VERSION 5.8 ;
BUSBITCHARS "[]" ;
DIVIDERCHAR "/" ;
UNITS
    DATABASE MICRONS 1000 ;
END UNITS

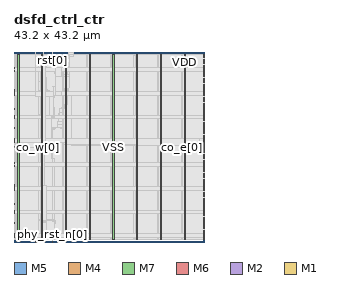
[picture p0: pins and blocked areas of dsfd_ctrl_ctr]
MACRO dsfd_ctrl_ctr
  FOREIGN dsfd_ctrl_ctr 0 0 ;
  CLASS BLOCK ;
  SIZE 43.2 BY 43.2 ;
  PIN ckh[0]
    DIRECTION INPUT ;
    USE SIGNAL ;
    PORT
      LAYER M5 ;
        RECT  6.72 43.008 6.744 43.2 ;
    END
  END ckh[0]
  PIN cks[0]
    DIRECTION INPUT ;
    USE SIGNAL ;
    PORT
      LAYER M5 ;
        RECT  4.8 43.008 4.824 43.2 ;
    END
  END cks[0]
  PIN co_e[0]
    DIRECTION INPUT ;
    USE SIGNAL ;
    PORT
      LAYER M4 ;
        RECT  43.008 21.552 43.2 21.576 ;
    END
  END co_e[0]
  PIN co_e[1]
    DIRECTION INPUT ;
    USE SIGNAL ;
    PORT
      LAYER M4 ;
        RECT  43.008 21.936 43.2 21.96 ;
    END
  END co_e[1]
  PIN co_w[0]
    DIRECTION INPUT ;
    USE SIGNAL ;
    PORT
      LAYER M4 ;
        RECT  0 21.552 0.192 21.576 ;
    END
  END co_w[0]
  PIN co_w[1]
    DIRECTION INPUT ;
    USE SIGNAL ;
    PORT
      LAYER M4 ;
        RECT  0 21.936 0.192 21.96 ;
    END
  END co_w[1]
  PIN k_oor[0]
    DIRECTION INPUT ;
    USE SIGNAL ;
    PORT
      LAYER M5 ;
        RECT  4.8 0 4.824 0.192 ;
    END
  END k_oor[0]
  PIN phy_rst_n[0]
    DIRECTION OUTPUT ;
    USE SIGNAL ;
    PORT
      LAYER M5 ;
        RECT  8.64 0 8.664 0.192 ;
    END
  END phy_rst_n[0]
  PIN rst[0]
    DIRECTION INPUT ;
    USE SIGNAL ;
    PORT
      LAYER M5 ;
        RECT  8.64 43.008 8.664 43.2 ;
    END
  END rst[0]
  PIN st[0]
    DIRECTION OUTPUT ;
    USE SIGNAL ;
    PORT
      LAYER M5 ;
        RECT  12.48 43.008 12.504 43.2 ;
    END
  END st[0]
  PIN st[1]
    DIRECTION OUTPUT ;
    USE SIGNAL ;
    PORT
      LAYER M5 ;
        RECT  13.44 43.008 13.464 43.2 ;
    END
  END st[1]
  PIN w_oor[0]
    DIRECTION INPUT ;
    USE SIGNAL ;
    PORT
      LAYER M5 ;
        RECT  6.72 0 6.744 0.192 ;
    END
  END w_oor[0]
  PIN VDD
    DIRECTION INOUT ;
    USE POWER ;
    PORT
      LAYER M7 ;
        RECT  38.656 0.531 38.944 42.669 ;
        RECT  27.856 0.531 28.144 42.669 ;
        RECT  17.056 0.531 17.344 42.669 ;
        RECT  6.256 0.531 6.544 42.669 ;
      LAYER M6 ;
        RECT  43.168 39.372 43.2 39.66 ;
        RECT  0 39.372 0.032 39.66 ;
        RECT  43.168 33.972 43.2 34.26 ;
        RECT  0 33.972 0.032 34.26 ;
        RECT  43.168 28.572 43.2 28.86 ;
        RECT  0 28.572 0.032 28.86 ;
        RECT  43.168 23.172 43.2 23.46 ;
        RECT  0 23.172 0.032 23.46 ;
        RECT  43.168 17.772 43.2 18.06 ;
        RECT  0 17.772 0.032 18.06 ;
        RECT  43.168 12.372 43.2 12.66 ;
        RECT  0 12.372 0.032 12.66 ;
        RECT  43.168 6.972 43.2 7.26 ;
        RECT  0 6.972 0.032 7.26 ;
        RECT  43.168 1.572 43.2 1.86 ;
        RECT  0 1.572 0.032 1.86 ;
      LAYER M2 ;
        RECT  43.182 42.381 43.2 42.399 ;
        RECT  0 42.381 0.018 42.399 ;
        RECT  43.182 41.841 43.2 41.859 ;
        RECT  0 41.841 0.018 41.859 ;
        RECT  43.182 41.301 43.2 41.319 ;
        RECT  0 41.301 0.018 41.319 ;
        RECT  43.182 40.761 43.2 40.779 ;
        RECT  0 40.761 0.018 40.779 ;
        RECT  43.182 40.221 43.2 40.239 ;
        RECT  0 40.221 0.018 40.239 ;
        RECT  43.182 39.681 43.2 39.699 ;
        RECT  0 39.681 0.018 39.699 ;
        RECT  43.182 39.141 43.2 39.159 ;
        RECT  0 39.141 0.018 39.159 ;
        RECT  43.182 38.601 43.2 38.619 ;
        RECT  0 38.601 0.018 38.619 ;
        RECT  43.182 38.061 43.2 38.079 ;
        RECT  0 38.061 0.018 38.079 ;
        RECT  43.182 37.521 43.2 37.539 ;
        RECT  0 37.521 0.018 37.539 ;
        RECT  43.182 36.981 43.2 36.999 ;
        RECT  0 36.981 0.018 36.999 ;
        RECT  43.182 36.441 43.2 36.459 ;
        RECT  0 36.441 0.018 36.459 ;
        RECT  43.182 35.901 43.2 35.919 ;
        RECT  0 35.901 0.018 35.919 ;
        RECT  43.182 35.361 43.2 35.379 ;
        RECT  0 35.361 0.018 35.379 ;
        RECT  43.182 34.821 43.2 34.839 ;
        RECT  0 34.821 0.018 34.839 ;
        RECT  43.182 34.281 43.2 34.299 ;
        RECT  0 34.281 0.018 34.299 ;
        RECT  43.182 33.741 43.2 33.759 ;
        RECT  0 33.741 0.018 33.759 ;
        RECT  43.182 33.201 43.2 33.219 ;
        RECT  0 33.201 0.018 33.219 ;
        RECT  43.182 32.661 43.2 32.679 ;
        RECT  0 32.661 0.018 32.679 ;
        RECT  43.182 32.121 43.2 32.139 ;
        RECT  0 32.121 0.018 32.139 ;
        RECT  43.182 31.581 43.2 31.599 ;
        RECT  0 31.581 0.018 31.599 ;
        RECT  43.182 31.041 43.2 31.059 ;
        RECT  0 31.041 0.018 31.059 ;
        RECT  43.182 30.501 43.2 30.519 ;
        RECT  0 30.501 0.018 30.519 ;
        RECT  43.182 29.961 43.2 29.979 ;
        RECT  0 29.961 0.018 29.979 ;
        RECT  43.182 29.421 43.2 29.439 ;
        RECT  0 29.421 0.018 29.439 ;
        RECT  43.182 28.881 43.2 28.899 ;
        RECT  0 28.881 0.018 28.899 ;
        RECT  43.182 28.341 43.2 28.359 ;
        RECT  0 28.341 0.018 28.359 ;
        RECT  43.182 27.801 43.2 27.819 ;
        RECT  0 27.801 0.018 27.819 ;
        RECT  43.182 27.261 43.2 27.279 ;
        RECT  0 27.261 0.018 27.279 ;
        RECT  43.182 26.721 43.2 26.739 ;
        RECT  0 26.721 0.018 26.739 ;
        RECT  43.182 26.181 43.2 26.199 ;
        RECT  0 26.181 0.018 26.199 ;
        RECT  43.182 25.641 43.2 25.659 ;
        RECT  0 25.641 0.018 25.659 ;
        RECT  43.182 25.101 43.2 25.119 ;
        RECT  0 25.101 0.018 25.119 ;
        RECT  43.182 24.561 43.2 24.579 ;
        RECT  0 24.561 0.018 24.579 ;
        RECT  43.182 24.021 43.2 24.039 ;
        RECT  0 24.021 0.018 24.039 ;
        RECT  43.182 23.481 43.2 23.499 ;
        RECT  0 23.481 0.018 23.499 ;
        RECT  43.182 22.941 43.2 22.959 ;
        RECT  0 22.941 0.018 22.959 ;
        RECT  43.182 22.401 43.2 22.419 ;
        RECT  0 22.401 0.018 22.419 ;
        RECT  43.182 21.861 43.2 21.879 ;
        RECT  0 21.861 0.018 21.879 ;
        RECT  43.182 21.321 43.2 21.339 ;
        RECT  0 21.321 0.018 21.339 ;
        RECT  43.182 20.781 43.2 20.799 ;
        RECT  0 20.781 0.018 20.799 ;
        RECT  43.182 20.241 43.2 20.259 ;
        RECT  0 20.241 0.018 20.259 ;
        RECT  43.182 19.701 43.2 19.719 ;
        RECT  0 19.701 0.018 19.719 ;
        RECT  43.182 19.161 43.2 19.179 ;
        RECT  0 19.161 0.018 19.179 ;
        RECT  43.182 18.621 43.2 18.639 ;
        RECT  0 18.621 0.018 18.639 ;
        RECT  43.182 18.081 43.2 18.099 ;
        RECT  0 18.081 0.018 18.099 ;
        RECT  43.182 17.541 43.2 17.559 ;
        RECT  0 17.541 0.018 17.559 ;
        RECT  43.182 17.001 43.2 17.019 ;
        RECT  0 17.001 0.018 17.019 ;
        RECT  43.182 16.461 43.2 16.479 ;
        RECT  0 16.461 0.018 16.479 ;
        RECT  43.182 15.921 43.2 15.939 ;
        RECT  0 15.921 0.018 15.939 ;
        RECT  43.182 15.381 43.2 15.399 ;
        RECT  0 15.381 0.018 15.399 ;
        RECT  43.182 14.841 43.2 14.859 ;
        RECT  0 14.841 0.018 14.859 ;
        RECT  43.182 14.301 43.2 14.319 ;
        RECT  0 14.301 0.018 14.319 ;
        RECT  43.182 13.761 43.2 13.779 ;
        RECT  0 13.761 0.018 13.779 ;
        RECT  43.182 13.221 43.2 13.239 ;
        RECT  0 13.221 0.018 13.239 ;
        RECT  43.182 12.681 43.2 12.699 ;
        RECT  0 12.681 0.018 12.699 ;
        RECT  43.182 12.141 43.2 12.159 ;
        RECT  0 12.141 0.018 12.159 ;
        RECT  43.182 11.601 43.2 11.619 ;
        RECT  0 11.601 0.018 11.619 ;
        RECT  43.182 11.061 43.2 11.079 ;
        RECT  0 11.061 0.018 11.079 ;
        RECT  43.182 10.521 43.2 10.539 ;
        RECT  0 10.521 0.018 10.539 ;
        RECT  43.182 9.981 43.2 9.999 ;
        RECT  0 9.981 0.018 9.999 ;
        RECT  43.182 9.441 43.2 9.459 ;
        RECT  0 9.441 0.018 9.459 ;
        RECT  43.182 8.901 43.2 8.919 ;
        RECT  0 8.901 0.018 8.919 ;
        RECT  43.182 8.361 43.2 8.379 ;
        RECT  0 8.361 0.018 8.379 ;
        RECT  43.182 7.821 43.2 7.839 ;
        RECT  0 7.821 0.018 7.839 ;
        RECT  43.182 7.281 43.2 7.299 ;
        RECT  0 7.281 0.018 7.299 ;
        RECT  43.182 6.741 43.2 6.759 ;
        RECT  0 6.741 0.018 6.759 ;
        RECT  43.182 6.201 43.2 6.219 ;
        RECT  0 6.201 0.018 6.219 ;
        RECT  43.182 5.661 43.2 5.679 ;
        RECT  0 5.661 0.018 5.679 ;
        RECT  43.182 5.121 43.2 5.139 ;
        RECT  0 5.121 0.018 5.139 ;
        RECT  43.182 4.581 43.2 4.599 ;
        RECT  0 4.581 0.018 4.599 ;
        RECT  43.182 4.041 43.2 4.059 ;
        RECT  0 4.041 0.018 4.059 ;
        RECT  43.182 3.501 43.2 3.519 ;
        RECT  0 3.501 0.018 3.519 ;
        RECT  43.182 2.961 43.2 2.979 ;
        RECT  0 2.961 0.018 2.979 ;
        RECT  43.182 2.421 43.2 2.439 ;
        RECT  0 2.421 0.018 2.439 ;
        RECT  43.182 1.881 43.2 1.899 ;
        RECT  0 1.881 0.018 1.899 ;
        RECT  43.182 1.341 43.2 1.359 ;
        RECT  0 1.341 0.018 1.359 ;
        RECT  43.182 0.801 43.2 0.819 ;
        RECT  0 0.801 0.018 0.819 ;
      LAYER M1 ;
        RECT  43.182 42.381 43.2 42.399 ;
        RECT  0 42.381 0.018 42.399 ;
        RECT  43.182 41.841 43.2 41.859 ;
        RECT  0 41.841 0.018 41.859 ;
        RECT  43.182 41.301 43.2 41.319 ;
        RECT  0 41.301 0.018 41.319 ;
        RECT  43.182 40.761 43.2 40.779 ;
        RECT  0 40.761 0.018 40.779 ;
        RECT  43.182 40.221 43.2 40.239 ;
        RECT  0 40.221 0.018 40.239 ;
        RECT  43.182 39.681 43.2 39.699 ;
        RECT  0 39.681 0.018 39.699 ;
        RECT  43.182 39.141 43.2 39.159 ;
        RECT  0 39.141 0.018 39.159 ;
        RECT  43.182 38.601 43.2 38.619 ;
        RECT  0 38.601 0.018 38.619 ;
        RECT  43.182 38.061 43.2 38.079 ;
        RECT  0 38.061 0.018 38.079 ;
        RECT  43.182 37.521 43.2 37.539 ;
        RECT  0 37.521 0.018 37.539 ;
        RECT  43.182 36.981 43.2 36.999 ;
        RECT  0 36.981 0.018 36.999 ;
        RECT  43.182 36.441 43.2 36.459 ;
        RECT  0 36.441 0.018 36.459 ;
        RECT  43.182 35.901 43.2 35.919 ;
        RECT  0 35.901 0.018 35.919 ;
        RECT  43.182 35.361 43.2 35.379 ;
        RECT  0 35.361 0.018 35.379 ;
        RECT  43.182 34.821 43.2 34.839 ;
        RECT  0 34.821 0.018 34.839 ;
        RECT  43.182 34.281 43.2 34.299 ;
        RECT  0 34.281 0.018 34.299 ;
        RECT  43.182 33.741 43.2 33.759 ;
        RECT  0 33.741 0.018 33.759 ;
        RECT  43.182 33.201 43.2 33.219 ;
        RECT  0 33.201 0.018 33.219 ;
        RECT  43.182 32.661 43.2 32.679 ;
        RECT  0 32.661 0.018 32.679 ;
        RECT  43.182 32.121 43.2 32.139 ;
        RECT  0 32.121 0.018 32.139 ;
        RECT  43.182 31.581 43.2 31.599 ;
        RECT  0 31.581 0.018 31.599 ;
        RECT  43.182 31.041 43.2 31.059 ;
        RECT  0 31.041 0.018 31.059 ;
        RECT  43.182 30.501 43.2 30.519 ;
        RECT  0 30.501 0.018 30.519 ;
        RECT  43.182 29.961 43.2 29.979 ;
        RECT  0 29.961 0.018 29.979 ;
        RECT  43.182 29.421 43.2 29.439 ;
        RECT  0 29.421 0.018 29.439 ;
        RECT  43.182 28.881 43.2 28.899 ;
        RECT  0 28.881 0.018 28.899 ;
        RECT  43.182 28.341 43.2 28.359 ;
        RECT  0 28.341 0.018 28.359 ;
        RECT  43.182 27.801 43.2 27.819 ;
        RECT  0 27.801 0.018 27.819 ;
        RECT  43.182 27.261 43.2 27.279 ;
        RECT  0 27.261 0.018 27.279 ;
        RECT  43.182 26.721 43.2 26.739 ;
        RECT  0 26.721 0.018 26.739 ;
        RECT  43.182 26.181 43.2 26.199 ;
        RECT  0 26.181 0.018 26.199 ;
        RECT  43.182 25.641 43.2 25.659 ;
        RECT  0 25.641 0.018 25.659 ;
        RECT  43.182 25.101 43.2 25.119 ;
        RECT  0 25.101 0.018 25.119 ;
        RECT  43.182 24.561 43.2 24.579 ;
        RECT  0 24.561 0.018 24.579 ;
        RECT  43.182 24.021 43.2 24.039 ;
        RECT  0 24.021 0.018 24.039 ;
        RECT  43.182 23.481 43.2 23.499 ;
        RECT  0 23.481 0.018 23.499 ;
        RECT  43.182 22.941 43.2 22.959 ;
        RECT  0 22.941 0.018 22.959 ;
        RECT  43.182 22.401 43.2 22.419 ;
        RECT  0 22.401 0.018 22.419 ;
        RECT  43.182 21.861 43.2 21.879 ;
        RECT  0 21.861 0.018 21.879 ;
        RECT  43.182 21.321 43.2 21.339 ;
        RECT  0 21.321 0.018 21.339 ;
        RECT  43.182 20.781 43.2 20.799 ;
        RECT  0 20.781 0.018 20.799 ;
        RECT  43.182 20.241 43.2 20.259 ;
        RECT  0 20.241 0.018 20.259 ;
        RECT  43.182 19.701 43.2 19.719 ;
        RECT  0 19.701 0.018 19.719 ;
        RECT  43.182 19.161 43.2 19.179 ;
        RECT  0 19.161 0.018 19.179 ;
        RECT  43.182 18.621 43.2 18.639 ;
        RECT  0 18.621 0.018 18.639 ;
        RECT  43.182 18.081 43.2 18.099 ;
        RECT  0 18.081 0.018 18.099 ;
        RECT  43.182 17.541 43.2 17.559 ;
        RECT  0 17.541 0.018 17.559 ;
        RECT  43.182 17.001 43.2 17.019 ;
        RECT  0 17.001 0.018 17.019 ;
        RECT  43.182 16.461 43.2 16.479 ;
        RECT  0 16.461 0.018 16.479 ;
        RECT  43.182 15.921 43.2 15.939 ;
        RECT  0 15.921 0.018 15.939 ;
        RECT  43.182 15.381 43.2 15.399 ;
        RECT  0 15.381 0.018 15.399 ;
        RECT  43.182 14.841 43.2 14.859 ;
        RECT  0 14.841 0.018 14.859 ;
        RECT  43.182 14.301 43.2 14.319 ;
        RECT  0 14.301 0.018 14.319 ;
        RECT  43.182 13.761 43.2 13.779 ;
        RECT  0 13.761 0.018 13.779 ;
        RECT  43.182 13.221 43.2 13.239 ;
        RECT  0 13.221 0.018 13.239 ;
        RECT  43.182 12.681 43.2 12.699 ;
        RECT  0 12.681 0.018 12.699 ;
        RECT  43.182 12.141 43.2 12.159 ;
        RECT  0 12.141 0.018 12.159 ;
        RECT  43.182 11.601 43.2 11.619 ;
        RECT  0 11.601 0.018 11.619 ;
        RECT  43.182 11.061 43.2 11.079 ;
        RECT  0 11.061 0.018 11.079 ;
        RECT  43.182 10.521 43.2 10.539 ;
        RECT  0 10.521 0.018 10.539 ;
        RECT  43.182 9.981 43.2 9.999 ;
        RECT  0 9.981 0.018 9.999 ;
        RECT  43.182 9.441 43.2 9.459 ;
        RECT  0 9.441 0.018 9.459 ;
        RECT  43.182 8.901 43.2 8.919 ;
        RECT  0 8.901 0.018 8.919 ;
        RECT  43.182 8.361 43.2 8.379 ;
        RECT  0 8.361 0.018 8.379 ;
        RECT  43.182 7.821 43.2 7.839 ;
        RECT  0 7.821 0.018 7.839 ;
        RECT  43.182 7.281 43.2 7.299 ;
        RECT  0 7.281 0.018 7.299 ;
        RECT  43.182 6.741 43.2 6.759 ;
        RECT  0 6.741 0.018 6.759 ;
        RECT  43.182 6.201 43.2 6.219 ;
        RECT  0 6.201 0.018 6.219 ;
        RECT  43.182 5.661 43.2 5.679 ;
        RECT  0 5.661 0.018 5.679 ;
        RECT  43.182 5.121 43.2 5.139 ;
        RECT  0 5.121 0.018 5.139 ;
        RECT  43.182 4.581 43.2 4.599 ;
        RECT  0 4.581 0.018 4.599 ;
        RECT  43.182 4.041 43.2 4.059 ;
        RECT  0 4.041 0.018 4.059 ;
        RECT  43.182 3.501 43.2 3.519 ;
        RECT  0 3.501 0.018 3.519 ;
        RECT  43.182 2.961 43.2 2.979 ;
        RECT  0 2.961 0.018 2.979 ;
        RECT  43.182 2.421 43.2 2.439 ;
        RECT  0 2.421 0.018 2.439 ;
        RECT  43.182 1.881 43.2 1.899 ;
        RECT  0 1.881 0.018 1.899 ;
        RECT  43.182 1.341 43.2 1.359 ;
        RECT  0 1.341 0.018 1.359 ;
        RECT  43.182 0.801 43.2 0.819 ;
        RECT  0 0.801 0.018 0.819 ;
    END
  END VDD
  PIN VSS
    DIRECTION INOUT ;
    USE GROUND ;
    PORT
      LAYER M7 ;
        RECT  33.256 0.531 33.544 42.669 ;
        RECT  22.456 0.531 22.744 42.669 ;
        RECT  11.656 0.531 11.944 42.669 ;
        RECT  0.856 0.531 1.144 42.669 ;
      LAYER M6 ;
        RECT  43.168 38.796 43.2 39.084 ;
        RECT  0 38.796 0.032 39.084 ;
        RECT  43.168 33.396 43.2 33.684 ;
        RECT  0 33.396 0.032 33.684 ;
        RECT  43.168 27.996 43.2 28.284 ;
        RECT  0 27.996 0.032 28.284 ;
        RECT  43.168 22.596 43.2 22.884 ;
        RECT  0 22.596 0.032 22.884 ;
        RECT  43.168 17.196 43.2 17.484 ;
        RECT  0 17.196 0.032 17.484 ;
        RECT  43.168 11.796 43.2 12.084 ;
        RECT  0 11.796 0.032 12.084 ;
        RECT  43.168 6.396 43.2 6.684 ;
        RECT  0 6.396 0.032 6.684 ;
        RECT  43.168 0.996 43.2 1.284 ;
        RECT  0 0.996 0.032 1.284 ;
      LAYER M2 ;
        RECT  43.182 42.651 43.2 42.669 ;
        RECT  0 42.651 0.018 42.669 ;
        RECT  43.182 42.111 43.2 42.129 ;
        RECT  0 42.111 0.018 42.129 ;
        RECT  43.182 41.571 43.2 41.589 ;
        RECT  0 41.571 0.018 41.589 ;
        RECT  43.182 41.031 43.2 41.049 ;
        RECT  0 41.031 0.018 41.049 ;
        RECT  43.182 40.491 43.2 40.509 ;
        RECT  0 40.491 0.018 40.509 ;
        RECT  43.182 39.951 43.2 39.969 ;
        RECT  0 39.951 0.018 39.969 ;
        RECT  43.182 39.411 43.2 39.429 ;
        RECT  0 39.411 0.018 39.429 ;
        RECT  43.182 38.871 43.2 38.889 ;
        RECT  0 38.871 0.018 38.889 ;
        RECT  43.182 38.331 43.2 38.349 ;
        RECT  0 38.331 0.018 38.349 ;
        RECT  43.182 37.791 43.2 37.809 ;
        RECT  0 37.791 0.018 37.809 ;
        RECT  43.182 37.251 43.2 37.269 ;
        RECT  0 37.251 0.018 37.269 ;
        RECT  43.182 36.711 43.2 36.729 ;
        RECT  0 36.711 0.018 36.729 ;
        RECT  43.182 36.171 43.2 36.189 ;
        RECT  0 36.171 0.018 36.189 ;
        RECT  43.182 35.631 43.2 35.649 ;
        RECT  0 35.631 0.018 35.649 ;
        RECT  43.182 35.091 43.2 35.109 ;
        RECT  0 35.091 0.018 35.109 ;
        RECT  43.182 34.551 43.2 34.569 ;
        RECT  0 34.551 0.018 34.569 ;
        RECT  43.182 34.011 43.2 34.029 ;
        RECT  0 34.011 0.018 34.029 ;
        RECT  43.182 33.471 43.2 33.489 ;
        RECT  0 33.471 0.018 33.489 ;
        RECT  43.182 32.931 43.2 32.949 ;
        RECT  0 32.931 0.018 32.949 ;
        RECT  43.182 32.391 43.2 32.409 ;
        RECT  0 32.391 0.018 32.409 ;
        RECT  43.182 31.851 43.2 31.869 ;
        RECT  0 31.851 0.018 31.869 ;
        RECT  43.182 31.311 43.2 31.329 ;
        RECT  0 31.311 0.018 31.329 ;
        RECT  43.182 30.771 43.2 30.789 ;
        RECT  0 30.771 0.018 30.789 ;
        RECT  43.182 30.231 43.2 30.249 ;
        RECT  0 30.231 0.018 30.249 ;
        RECT  43.182 29.691 43.2 29.709 ;
        RECT  0 29.691 0.018 29.709 ;
        RECT  43.182 29.151 43.2 29.169 ;
        RECT  0 29.151 0.018 29.169 ;
        RECT  43.182 28.611 43.2 28.629 ;
        RECT  0 28.611 0.018 28.629 ;
        RECT  43.182 28.071 43.2 28.089 ;
        RECT  0 28.071 0.018 28.089 ;
        RECT  43.182 27.531 43.2 27.549 ;
        RECT  0 27.531 0.018 27.549 ;
        RECT  43.182 26.991 43.2 27.009 ;
        RECT  0 26.991 0.018 27.009 ;
        RECT  43.182 26.451 43.2 26.469 ;
        RECT  0 26.451 0.018 26.469 ;
        RECT  43.182 25.911 43.2 25.929 ;
        RECT  0 25.911 0.018 25.929 ;
        RECT  43.182 25.371 43.2 25.389 ;
        RECT  0 25.371 0.018 25.389 ;
        RECT  43.182 24.831 43.2 24.849 ;
        RECT  0 24.831 0.018 24.849 ;
        RECT  43.182 24.291 43.2 24.309 ;
        RECT  0 24.291 0.018 24.309 ;
        RECT  43.182 23.751 43.2 23.769 ;
        RECT  0 23.751 0.018 23.769 ;
        RECT  43.182 23.211 43.2 23.229 ;
        RECT  0 23.211 0.018 23.229 ;
        RECT  43.182 22.671 43.2 22.689 ;
        RECT  0 22.671 0.018 22.689 ;
        RECT  43.182 22.131 43.2 22.149 ;
        RECT  0 22.131 0.018 22.149 ;
        RECT  43.182 21.591 43.2 21.609 ;
        RECT  0 21.591 0.018 21.609 ;
        RECT  43.182 21.051 43.2 21.069 ;
        RECT  0 21.051 0.018 21.069 ;
        RECT  43.182 20.511 43.2 20.529 ;
        RECT  0 20.511 0.018 20.529 ;
        RECT  43.182 19.971 43.2 19.989 ;
        RECT  0 19.971 0.018 19.989 ;
        RECT  43.182 19.431 43.2 19.449 ;
        RECT  0 19.431 0.018 19.449 ;
        RECT  43.182 18.891 43.2 18.909 ;
        RECT  0 18.891 0.018 18.909 ;
        RECT  43.182 18.351 43.2 18.369 ;
        RECT  0 18.351 0.018 18.369 ;
        RECT  43.182 17.811 43.2 17.829 ;
        RECT  0 17.811 0.018 17.829 ;
        RECT  43.182 17.271 43.2 17.289 ;
        RECT  0 17.271 0.018 17.289 ;
        RECT  43.182 16.731 43.2 16.749 ;
        RECT  0 16.731 0.018 16.749 ;
        RECT  43.182 16.191 43.2 16.209 ;
        RECT  0 16.191 0.018 16.209 ;
        RECT  43.182 15.651 43.2 15.669 ;
        RECT  0 15.651 0.018 15.669 ;
        RECT  43.182 15.111 43.2 15.129 ;
        RECT  0 15.111 0.018 15.129 ;
        RECT  43.182 14.571 43.2 14.589 ;
        RECT  0 14.571 0.018 14.589 ;
        RECT  43.182 14.031 43.2 14.049 ;
        RECT  0 14.031 0.018 14.049 ;
        RECT  43.182 13.491 43.2 13.509 ;
        RECT  0 13.491 0.018 13.509 ;
        RECT  43.182 12.951 43.2 12.969 ;
        RECT  0 12.951 0.018 12.969 ;
        RECT  43.182 12.411 43.2 12.429 ;
        RECT  0 12.411 0.018 12.429 ;
        RECT  43.182 11.871 43.2 11.889 ;
        RECT  0 11.871 0.018 11.889 ;
        RECT  43.182 11.331 43.2 11.349 ;
        RECT  0 11.331 0.018 11.349 ;
        RECT  43.182 10.791 43.2 10.809 ;
        RECT  0 10.791 0.018 10.809 ;
        RECT  43.182 10.251 43.2 10.269 ;
        RECT  0 10.251 0.018 10.269 ;
        RECT  43.182 9.711 43.2 9.729 ;
        RECT  0 9.711 0.018 9.729 ;
        RECT  43.182 9.171 43.2 9.189 ;
        RECT  0 9.171 0.018 9.189 ;
        RECT  43.182 8.631 43.2 8.649 ;
        RECT  0 8.631 0.018 8.649 ;
        RECT  43.182 8.091 43.2 8.109 ;
        RECT  0 8.091 0.018 8.109 ;
        RECT  43.182 7.551 43.2 7.569 ;
        RECT  0 7.551 0.018 7.569 ;
        RECT  43.182 7.011 43.2 7.029 ;
        RECT  0 7.011 0.018 7.029 ;
        RECT  43.182 6.471 43.2 6.489 ;
        RECT  0 6.471 0.018 6.489 ;
        RECT  43.182 5.931 43.2 5.949 ;
        RECT  0 5.931 0.018 5.949 ;
        RECT  43.182 5.391 43.2 5.409 ;
        RECT  0 5.391 0.018 5.409 ;
        RECT  43.182 4.851 43.2 4.869 ;
        RECT  0 4.851 0.018 4.869 ;
        RECT  43.182 4.311 43.2 4.329 ;
        RECT  0 4.311 0.018 4.329 ;
        RECT  43.182 3.771 43.2 3.789 ;
        RECT  0 3.771 0.018 3.789 ;
        RECT  43.182 3.231 43.2 3.249 ;
        RECT  0 3.231 0.018 3.249 ;
        RECT  43.182 2.691 43.2 2.709 ;
        RECT  0 2.691 0.018 2.709 ;
        RECT  43.182 2.151 43.2 2.169 ;
        RECT  0 2.151 0.018 2.169 ;
        RECT  43.182 1.611 43.2 1.629 ;
        RECT  0 1.611 0.018 1.629 ;
        RECT  43.182 1.071 43.2 1.089 ;
        RECT  0 1.071 0.018 1.089 ;
        RECT  43.182 0.531 43.2 0.549 ;
        RECT  0 0.531 0.018 0.549 ;
      LAYER M1 ;
        RECT  43.182 42.651 43.2 42.669 ;
        RECT  0 42.651 0.018 42.669 ;
        RECT  43.182 42.111 43.2 42.129 ;
        RECT  0 42.111 0.018 42.129 ;
        RECT  43.182 41.571 43.2 41.589 ;
        RECT  0 41.571 0.018 41.589 ;
        RECT  43.182 41.031 43.2 41.049 ;
        RECT  0 41.031 0.018 41.049 ;
        RECT  43.182 40.491 43.2 40.509 ;
        RECT  0 40.491 0.018 40.509 ;
        RECT  43.182 39.951 43.2 39.969 ;
        RECT  0 39.951 0.018 39.969 ;
        RECT  43.182 39.411 43.2 39.429 ;
        RECT  0 39.411 0.018 39.429 ;
        RECT  43.182 38.871 43.2 38.889 ;
        RECT  0 38.871 0.018 38.889 ;
        RECT  43.182 38.331 43.2 38.349 ;
        RECT  0 38.331 0.018 38.349 ;
        RECT  43.182 37.791 43.2 37.809 ;
        RECT  0 37.791 0.018 37.809 ;
        RECT  43.182 37.251 43.2 37.269 ;
        RECT  0 37.251 0.018 37.269 ;
        RECT  43.182 36.711 43.2 36.729 ;
        RECT  0 36.711 0.018 36.729 ;
        RECT  43.182 36.171 43.2 36.189 ;
        RECT  0 36.171 0.018 36.189 ;
        RECT  43.182 35.631 43.2 35.649 ;
        RECT  0 35.631 0.018 35.649 ;
        RECT  43.182 35.091 43.2 35.109 ;
        RECT  0 35.091 0.018 35.109 ;
        RECT  43.182 34.551 43.2 34.569 ;
        RECT  0 34.551 0.018 34.569 ;
        RECT  43.182 34.011 43.2 34.029 ;
        RECT  0 34.011 0.018 34.029 ;
        RECT  43.182 33.471 43.2 33.489 ;
        RECT  0 33.471 0.018 33.489 ;
        RECT  43.182 32.931 43.2 32.949 ;
        RECT  0 32.931 0.018 32.949 ;
        RECT  43.182 32.391 43.2 32.409 ;
        RECT  0 32.391 0.018 32.409 ;
        RECT  43.182 31.851 43.2 31.869 ;
        RECT  0 31.851 0.018 31.869 ;
        RECT  43.182 31.311 43.2 31.329 ;
        RECT  0 31.311 0.018 31.329 ;
        RECT  43.182 30.771 43.2 30.789 ;
        RECT  0 30.771 0.018 30.789 ;
        RECT  43.182 30.231 43.2 30.249 ;
        RECT  0 30.231 0.018 30.249 ;
        RECT  43.182 29.691 43.2 29.709 ;
        RECT  0 29.691 0.018 29.709 ;
        RECT  43.182 29.151 43.2 29.169 ;
        RECT  0 29.151 0.018 29.169 ;
        RECT  43.182 28.611 43.2 28.629 ;
        RECT  0 28.611 0.018 28.629 ;
        RECT  43.182 28.071 43.2 28.089 ;
        RECT  0 28.071 0.018 28.089 ;
        RECT  43.182 27.531 43.2 27.549 ;
        RECT  0 27.531 0.018 27.549 ;
        RECT  43.182 26.991 43.2 27.009 ;
        RECT  0 26.991 0.018 27.009 ;
        RECT  43.182 26.451 43.2 26.469 ;
        RECT  0 26.451 0.018 26.469 ;
        RECT  43.182 25.911 43.2 25.929 ;
        RECT  0 25.911 0.018 25.929 ;
        RECT  43.182 25.371 43.2 25.389 ;
        RECT  0 25.371 0.018 25.389 ;
        RECT  43.182 24.831 43.2 24.849 ;
        RECT  0 24.831 0.018 24.849 ;
        RECT  43.182 24.291 43.2 24.309 ;
        RECT  0 24.291 0.018 24.309 ;
        RECT  43.182 23.751 43.2 23.769 ;
        RECT  0 23.751 0.018 23.769 ;
        RECT  43.182 23.211 43.2 23.229 ;
        RECT  0 23.211 0.018 23.229 ;
        RECT  43.182 22.671 43.2 22.689 ;
        RECT  0 22.671 0.018 22.689 ;
        RECT  43.182 22.131 43.2 22.149 ;
        RECT  0 22.131 0.018 22.149 ;
        RECT  43.182 21.591 43.2 21.609 ;
        RECT  0 21.591 0.018 21.609 ;
        RECT  43.182 21.051 43.2 21.069 ;
        RECT  0 21.051 0.018 21.069 ;
        RECT  43.182 20.511 43.2 20.529 ;
        RECT  0 20.511 0.018 20.529 ;
        RECT  43.182 19.971 43.2 19.989 ;
        RECT  0 19.971 0.018 19.989 ;
        RECT  43.182 19.431 43.2 19.449 ;
        RECT  0 19.431 0.018 19.449 ;
        RECT  43.182 18.891 43.2 18.909 ;
        RECT  0 18.891 0.018 18.909 ;
        RECT  43.182 18.351 43.2 18.369 ;
        RECT  0 18.351 0.018 18.369 ;
        RECT  43.182 17.811 43.2 17.829 ;
        RECT  0 17.811 0.018 17.829 ;
        RECT  43.182 17.271 43.2 17.289 ;
        RECT  0 17.271 0.018 17.289 ;
        RECT  43.182 16.731 43.2 16.749 ;
        RECT  0 16.731 0.018 16.749 ;
        RECT  43.182 16.191 43.2 16.209 ;
        RECT  0 16.191 0.018 16.209 ;
        RECT  43.182 15.651 43.2 15.669 ;
        RECT  0 15.651 0.018 15.669 ;
        RECT  43.182 15.111 43.2 15.129 ;
        RECT  0 15.111 0.018 15.129 ;
        RECT  43.182 14.571 43.2 14.589 ;
        RECT  0 14.571 0.018 14.589 ;
        RECT  43.182 14.031 43.2 14.049 ;
        RECT  0 14.031 0.018 14.049 ;
        RECT  43.182 13.491 43.2 13.509 ;
        RECT  0 13.491 0.018 13.509 ;
        RECT  43.182 12.951 43.2 12.969 ;
        RECT  0 12.951 0.018 12.969 ;
        RECT  43.182 12.411 43.2 12.429 ;
        RECT  0 12.411 0.018 12.429 ;
        RECT  43.182 11.871 43.2 11.889 ;
        RECT  0 11.871 0.018 11.889 ;
        RECT  43.182 11.331 43.2 11.349 ;
        RECT  0 11.331 0.018 11.349 ;
        RECT  43.182 10.791 43.2 10.809 ;
        RECT  0 10.791 0.018 10.809 ;
        RECT  43.182 10.251 43.2 10.269 ;
        RECT  0 10.251 0.018 10.269 ;
        RECT  43.182 9.711 43.2 9.729 ;
        RECT  0 9.711 0.018 9.729 ;
        RECT  43.182 9.171 43.2 9.189 ;
        RECT  0 9.171 0.018 9.189 ;
        RECT  43.182 8.631 43.2 8.649 ;
        RECT  0 8.631 0.018 8.649 ;
        RECT  43.182 8.091 43.2 8.109 ;
        RECT  0 8.091 0.018 8.109 ;
        RECT  43.182 7.551 43.2 7.569 ;
        RECT  0 7.551 0.018 7.569 ;
        RECT  43.182 7.011 43.2 7.029 ;
        RECT  0 7.011 0.018 7.029 ;
        RECT  43.182 6.471 43.2 6.489 ;
        RECT  0 6.471 0.018 6.489 ;
        RECT  43.182 5.931 43.2 5.949 ;
        RECT  0 5.931 0.018 5.949 ;
        RECT  43.182 5.391 43.2 5.409 ;
        RECT  0 5.391 0.018 5.409 ;
        RECT  43.182 4.851 43.2 4.869 ;
        RECT  0 4.851 0.018 4.869 ;
        RECT  43.182 4.311 43.2 4.329 ;
        RECT  0 4.311 0.018 4.329 ;
        RECT  43.182 3.771 43.2 3.789 ;
        RECT  0 3.771 0.018 3.789 ;
        RECT  43.182 3.231 43.2 3.249 ;
        RECT  0 3.231 0.018 3.249 ;
        RECT  43.182 2.691 43.2 2.709 ;
        RECT  0 2.691 0.018 2.709 ;
        RECT  43.182 2.151 43.2 2.169 ;
        RECT  0 2.151 0.018 2.169 ;
        RECT  43.182 1.611 43.2 1.629 ;
        RECT  0 1.611 0.018 1.629 ;
        RECT  43.182 1.071 43.2 1.089 ;
        RECT  0 1.071 0.018 1.089 ;
        RECT  43.182 0.531 43.2 0.549 ;
        RECT  0 0.531 0.018 0.549 ;
    END
  END VSS
  OBS
    LAYER RVTN ;
     RECT  0 0.54 43.2 0.675 ;
     RECT  0 0.945 43.2 1.215 ;
     RECT  0 1.485 43.2 1.755 ;
     RECT  0 2.025 43.2 2.295 ;
     RECT  0 2.565 43.2 2.835 ;
     RECT  0 3.105 43.2 3.375 ;
     RECT  0 3.645 43.2 3.915 ;
     RECT  0 4.185 43.2 4.455 ;
     RECT  0 4.725 43.2 4.995 ;
     RECT  0 5.265 43.2 5.535 ;
     RECT  0 5.805 43.2 6.075 ;
     RECT  0 6.345 43.2 6.615 ;
     RECT  0 6.885 43.2 7.155 ;
     RECT  0 7.425 43.2 7.695 ;
     RECT  0 7.965 43.2 8.235 ;
     RECT  0 8.505 43.2 8.775 ;
     RECT  0 9.045 43.2 9.315 ;
     RECT  0 9.585 43.2 9.855 ;
     RECT  0 10.125 43.2 10.395 ;
     RECT  0 10.665 43.2 10.935 ;
     RECT  0 11.205 43.2 11.475 ;
     RECT  0 11.745 43.2 12.015 ;
     RECT  0 12.285 43.2 12.555 ;
     RECT  0 12.825 43.2 13.095 ;
     RECT  0 13.365 43.2 13.635 ;
     RECT  0 13.905 43.2 14.175 ;
     RECT  0 14.445 43.2 14.715 ;
     RECT  0 14.985 43.2 15.255 ;
     RECT  0 15.525 43.2 15.795 ;
     RECT  0 16.065 43.2 16.335 ;
     RECT  0 16.605 43.2 16.875 ;
     RECT  0 17.145 43.2 17.415 ;
     RECT  0 17.685 43.2 17.955 ;
     RECT  0 18.225 43.2 18.495 ;
     RECT  0 18.765 43.2 19.035 ;
     RECT  0 19.305 43.2 19.575 ;
     RECT  0 19.845 43.2 20.115 ;
     RECT  0 20.385 43.2 20.655 ;
     RECT  0 20.925 43.2 21.195 ;
     RECT  0 21.465 43.2 21.735 ;
     RECT  0 22.005 43.2 22.275 ;
     RECT  0 22.545 43.2 22.815 ;
     RECT  0 23.085 43.2 23.355 ;
     RECT  0 23.625 43.2 23.895 ;
     RECT  0 24.165 43.2 24.435 ;
     RECT  0 24.705 43.2 24.975 ;
     RECT  0 25.245 43.2 25.515 ;
     RECT  0 25.785 43.2 26.055 ;
     RECT  0 26.325 43.2 26.595 ;
     RECT  0 26.865 43.2 27.135 ;
     RECT  0 27.405 43.2 27.675 ;
     RECT  0 27.945 43.2 28.215 ;
     RECT  0 28.485 43.2 28.755 ;
     RECT  0 29.025 43.2 29.295 ;
     RECT  0 29.565 43.2 29.835 ;
     RECT  0 30.105 43.2 30.375 ;
     RECT  0 30.645 43.2 30.915 ;
     RECT  0 31.185 43.2 31.455 ;
     RECT  0 31.725 43.2 31.995 ;
     RECT  0 32.265 43.2 32.535 ;
     RECT  0 32.805 43.2 33.075 ;
     RECT  0 33.345 43.2 33.615 ;
     RECT  0 33.885 43.2 34.155 ;
     RECT  0 34.425 43.2 34.695 ;
     RECT  0 34.965 43.2 35.235 ;
     RECT  0 35.505 43.2 35.775 ;
     RECT  0 36.045 43.2 36.315 ;
     RECT  0 36.585 43.2 36.855 ;
     RECT  0 37.125 43.2 37.395 ;
     RECT  0 37.665 43.2 37.935 ;
     RECT  0 38.205 43.2 38.475 ;
     RECT  0 38.745 43.2 39.015 ;
     RECT  0 39.285 43.2 39.555 ;
     RECT  0 39.825 43.2 40.095 ;
     RECT  0 40.365 43.2 40.635 ;
     RECT  0 40.905 43.2 41.175 ;
     RECT  0 41.445 43.2 41.715 ;
     RECT  0 41.985 43.2 42.255 ;
     RECT  0 42.525 43.2 42.66 ;
    LAYER RVTP ;
     RECT  0 0.675 43.2 0.945 ;
     RECT  0 1.215 43.2 1.485 ;
     RECT  0 1.755 43.2 2.025 ;
     RECT  0 2.295 43.2 2.565 ;
     RECT  0 2.835 43.2 3.105 ;
     RECT  0 3.375 43.2 3.645 ;
     RECT  0 3.915 43.2 4.185 ;
     RECT  0 4.455 43.2 4.725 ;
     RECT  0 4.995 43.2 5.265 ;
     RECT  0 5.535 43.2 5.805 ;
     RECT  0 6.075 43.2 6.345 ;
     RECT  0 6.615 43.2 6.885 ;
     RECT  0 7.155 43.2 7.425 ;
     RECT  0 7.695 43.2 7.965 ;
     RECT  0 8.235 43.2 8.505 ;
     RECT  0 8.775 43.2 9.045 ;
     RECT  0 9.315 43.2 9.585 ;
     RECT  0 9.855 43.2 10.125 ;
     RECT  0 10.395 43.2 10.665 ;
     RECT  0 10.935 43.2 11.205 ;
     RECT  0 11.475 43.2 11.745 ;
     RECT  0 12.015 43.2 12.285 ;
     RECT  0 12.555 43.2 12.825 ;
     RECT  0 13.095 43.2 13.365 ;
     RECT  0 13.635 43.2 13.905 ;
     RECT  0 14.175 43.2 14.445 ;
     RECT  0 14.715 43.2 14.985 ;
     RECT  0 15.255 43.2 15.525 ;
     RECT  0 15.795 43.2 16.065 ;
     RECT  0 16.335 43.2 16.605 ;
     RECT  0 16.875 43.2 17.145 ;
     RECT  0 17.415 43.2 17.685 ;
     RECT  0 17.955 43.2 18.225 ;
     RECT  0 18.495 43.2 18.765 ;
     RECT  0 19.035 43.2 19.305 ;
     RECT  0 19.575 43.2 19.845 ;
     RECT  0 20.115 43.2 20.385 ;
     RECT  0 20.655 43.2 20.925 ;
     RECT  0 21.195 43.2 21.465 ;
     RECT  0 21.735 43.2 22.005 ;
     RECT  0 22.275 43.2 22.545 ;
     RECT  0 22.815 43.2 23.085 ;
     RECT  0 23.355 43.2 23.625 ;
     RECT  0 23.895 43.2 24.165 ;
     RECT  0 24.435 43.2 24.705 ;
     RECT  0 24.975 43.2 25.245 ;
     RECT  0 25.515 43.2 25.785 ;
     RECT  0 26.055 43.2 26.325 ;
     RECT  0 26.595 43.2 26.865 ;
     RECT  0 27.135 43.2 27.405 ;
     RECT  0 27.675 43.2 27.945 ;
     RECT  0 28.215 43.2 28.485 ;
     RECT  0 28.755 43.2 29.025 ;
     RECT  0 29.295 43.2 29.565 ;
     RECT  0 29.835 43.2 30.105 ;
     RECT  0 30.375 43.2 30.645 ;
     RECT  0 30.915 43.2 31.185 ;
     RECT  0 31.455 43.2 31.725 ;
     RECT  0 31.995 43.2 32.265 ;
     RECT  0 32.535 43.2 32.805 ;
     RECT  0 33.075 43.2 33.345 ;
     RECT  0 33.615 43.2 33.885 ;
     RECT  0 34.155 43.2 34.425 ;
     RECT  0 34.695 43.2 34.965 ;
     RECT  0 35.235 43.2 35.505 ;
     RECT  0 35.775 43.2 36.045 ;
     RECT  0 36.315 43.2 36.585 ;
     RECT  0 36.855 43.2 37.125 ;
     RECT  0 37.395 43.2 37.665 ;
     RECT  0 37.935 43.2 38.205 ;
     RECT  0 38.475 43.2 38.745 ;
     RECT  0 39.015 43.2 39.285 ;
     RECT  0 39.555 43.2 39.825 ;
     RECT  0 40.095 43.2 40.365 ;
     RECT  0 40.635 43.2 40.905 ;
     RECT  0 41.175 43.2 41.445 ;
     RECT  0 41.715 43.2 41.985 ;
     RECT  0 42.255 43.2 42.525 ;
    LAYER M1 ;
     RECT  0 0.531 43.2 42.669 ;
    LAYER M2 ;
     RECT  0 0.531 43.2 42.669 ;
    LAYER M3 ;
     RECT  6.336 0.187 6.354 0.523 ;
     RECT  4.824 0.187 4.842 0.635 ;
     RECT  5.655 0.523 6.354 0.751 ;
     RECT  0.255 0.523 0.345 0.793 ;
     RECT  11.055 0.523 11.145 0.793 ;
     RECT  16.455 0.523 16.545 0.793 ;
     RECT  21.855 0.523 21.945 0.793 ;
     RECT  27.255 0.523 27.345 0.793 ;
     RECT  32.655 0.523 32.745 0.793 ;
     RECT  38.055 0.523 38.145 0.793 ;
     RECT  5.508 0.751 6.354 1.021 ;
     RECT  5.508 1.021 6.498 1.139 ;
     RECT  5.655 1.139 6.498 1.409 ;
     RECT  8.964 1.147 8.982 1.409 ;
     RECT  9.18 1.525 9.198 2.263 ;
     RECT  5.655 1.409 6.138 2.641 ;
     RECT  9.18 2.263 9.27 2.759 ;
     RECT  5.655 2.641 6.21 3.721 ;
     RECT  9.144 2.803 9.162 4.225 ;
     RECT  5.655 3.721 6.318 4.531 ;
     RECT  7.416 2.497 7.434 4.531 ;
     RECT  9.144 4.225 9.486 4.729 ;
     RECT  5.655 4.531 7.434 4.757 ;
     RECT  5.655 4.757 6.93 4.829 ;
     RECT  6.912 4.829 6.93 4.919 ;
     RECT  8.712 4.729 9.486 4.919 ;
     RECT  8.712 4.919 9.126 4.987 ;
     RECT  5.655 4.829 5.994 5.021 ;
     RECT  8.172 4.987 9.126 5.027 ;
     RECT  8.316 5.027 9.126 5.189 ;
     RECT  7.344 12.712 7.362 12.749 ;
     RECT  7.092 12.793 7.11 12.893 ;
     RECT  8.712 5.189 9.126 18.959 ;
     RECT  8.712 18.959 8.73 19.075 ;
     RECT  7.092 20.965 7.11 21.001 ;
     RECT  7.092 21.001 7.326 21.005 ;
     RECT  7.308 21.005 7.326 21.101 ;
     RECT  0.255 0.793 0.537 21.505 ;
     RECT  5.655 5.021 5.937 21.547 ;
     RECT  0.036 21.505 0.537 21.581 ;
     RECT  0.255 21.581 0.537 21.931 ;
     RECT  21.855 0.793 22.137 21.931 ;
     RECT  27.255 0.793 27.537 21.931 ;
     RECT  21.855 21.931 22.842 22.061 ;
     RECT  27.255 21.931 28.026 22.061 ;
     RECT  27.255 22.061 27.666 22.157 ;
     RECT  11.055 0.793 11.337 22.171 ;
     RECT  5.22 21.547 5.937 22.235 ;
     RECT  10.296 22.171 10.314 22.711 ;
     RECT  11.055 22.171 12.006 22.711 ;
     RECT  10.296 22.711 12.006 22.775 ;
     RECT  10.836 22.775 12.006 23.117 ;
     RECT  10.836 23.117 11.337 23.315 ;
     RECT  8.46 19.075 8.73 25.591 ;
     RECT  8.46 25.591 9.306 25.861 ;
     RECT  10.98 23.315 11.337 25.861 ;
     RECT  10.512 25.861 11.337 25.951 ;
     RECT  8.46 25.861 9.522 26.095 ;
     RECT  10.296 25.951 11.337 26.095 ;
     RECT  8.46 26.095 11.337 26.123 ;
     RECT  8.46 26.123 8.586 26.141 ;
     RECT  9.9 26.123 11.337 26.825 ;
     RECT  0.255 21.931 0.846 27.211 ;
     RECT  9.972 26.825 11.337 27.329 ;
     RECT  8.46 26.141 8.478 28.255 ;
     RECT  10.044 27.329 11.337 28.255 ;
     RECT  8.46 28.255 9.018 28.291 ;
     RECT  8.46 28.291 9.162 28.381 ;
     RECT  8.064 28.381 9.162 28.409 ;
     RECT  9.9 28.255 11.337 28.409 ;
     RECT  6.732 28.507 6.75 28.679 ;
     RECT  6.912 28.831 6.93 28.877 ;
     RECT  10.044 28.409 10.314 29.255 ;
     RECT  10.296 29.255 10.314 29.371 ;
     RECT  11.055 28.409 11.337 29.371 ;
     RECT  10.296 29.371 11.337 30.379 ;
     RECT  10.296 30.379 11.538 30.407 ;
     RECT  10.728 30.407 11.538 30.451 ;
     RECT  9.18 30.523 9.198 30.569 ;
     RECT  10.728 30.451 11.574 30.569 ;
     RECT  11.055 30.569 11.574 30.721 ;
     RECT  9 30.712 9.018 30.749 ;
     RECT  11.055 30.721 11.934 30.991 ;
     RECT  11.055 30.991 12.042 31.261 ;
     RECT  13.104 21.931 13.122 31.955 ;
     RECT  8.064 28.409 8.082 32.999 ;
     RECT  9.144 32.923 9.162 33.007 ;
     RECT  8.712 33.007 9.162 33.035 ;
     RECT  8.712 33.035 8.73 33.053 ;
     RECT  0.255 27.211 1.062 33.179 ;
     RECT  11.055 31.261 12.222 33.307 ;
     RECT  10.872 33.307 12.222 33.341 ;
     RECT  13.068 32.071 13.086 33.413 ;
     RECT  10.872 33.341 12.186 33.611 ;
     RECT  7.956 33.043 7.974 33.925 ;
     RECT  7.956 33.925 8.01 34.349 ;
     RECT  6.732 34.357 6.75 34.393 ;
     RECT  7.524 34.357 7.542 34.393 ;
     RECT  11.055 33.611 12.186 34.393 ;
     RECT  6.732 34.393 7.542 34.397 ;
     RECT  7.02 34.397 7.542 34.655 ;
     RECT  11.055 34.393 12.366 34.771 ;
     RECT  11.055 34.771 12.474 34.925 ;
     RECT  7.02 34.655 7.29 35.275 ;
     RECT  8.784 35.323 8.802 35.371 ;
     RECT  8.784 35.371 9.378 35.429 ;
     RECT  6.912 35.275 7.29 35.699 ;
     RECT  5.655 22.235 5.937 36.523 ;
     RECT  7.164 35.699 7.29 36.625 ;
     RECT  5.655 36.523 6.066 36.931 ;
     RECT  7.164 36.625 7.434 36.931 ;
     RECT  5.655 36.931 7.434 37.049 ;
     RECT  6.804 37.049 7.434 37.085 ;
     RECT  6.984 37.085 7.434 37.319 ;
     RECT  6.984 37.319 7.218 37.355 ;
     RECT  11.055 34.925 11.862 37.579 ;
     RECT  10.98 37.579 11.862 37.597 ;
     RECT  12.6 35.041 12.618 37.597 ;
     RECT  10.98 37.597 12.618 37.625 ;
     RECT  11.055 37.625 12.618 38.129 ;
     RECT  9.288 38.281 9.306 38.821 ;
     RECT  6.984 37.355 7.002 38.911 ;
     RECT  8.856 38.821 9.342 38.975 ;
     RECT  8.856 38.975 9.306 39.019 ;
     RECT  6.984 38.911 7.47 39.055 ;
     RECT  8.532 39.019 9.306 39.055 ;
     RECT  6.984 39.055 9.306 39.209 ;
     RECT  8.532 39.209 9.198 39.245 ;
     RECT  12.276 38.129 12.618 39.245 ;
     RECT  6.984 39.209 7.506 39.325 ;
     RECT  5.655 37.049 5.937 39.355 ;
     RECT  6.768 39.325 7.506 39.355 ;
     RECT  5.655 39.355 7.506 39.749 ;
     RECT  6.768 39.749 7.47 39.785 ;
     RECT  6.984 39.785 7.47 39.821 ;
     RECT  7.452 39.821 7.47 39.893 ;
     RECT  12.348 39.245 12.618 40.711 ;
     RECT  12.276 40.711 12.618 41.675 ;
     RECT  8.532 39.245 8.55 41.755 ;
     RECT  8.532 41.755 8.586 41.819 ;
     RECT  8.568 41.819 8.586 42.221 ;
     RECT  0.255 33.179 0.537 42.407 ;
     RECT  5.655 39.749 5.937 42.407 ;
     RECT  11.055 38.129 11.337 42.407 ;
     RECT  16.455 0.793 16.737 42.407 ;
     RECT  21.855 22.061 22.137 42.407 ;
     RECT  27.255 22.157 27.537 42.407 ;
     RECT  32.655 0.793 32.937 42.407 ;
     RECT  38.055 0.793 38.337 42.407 ;
     RECT  12.492 41.675 12.618 42.485 ;
     RECT  12.636 42.601 12.654 42.653 ;
     RECT  0.255 42.407 0.345 42.677 ;
     RECT  5.655 42.407 5.745 42.677 ;
     RECT  11.055 42.407 11.145 42.677 ;
     RECT  16.455 42.407 16.545 42.677 ;
     RECT  21.855 42.407 21.945 42.677 ;
     RECT  27.255 42.407 27.345 42.677 ;
     RECT  32.655 42.407 32.745 42.677 ;
     RECT  38.055 42.407 38.145 42.677 ;
    LAYER M4 ;
     RECT  0.025 21.552 0.156 21.576 ;
     RECT  0.156 21.552 0.248 21.96 ;
     RECT  0.248 0.528 0.352 42.672 ;
     RECT  0.352 0.798 0.544 42.402 ;
     RECT  0.544 21.552 0.857 21.96 ;
     RECT  4.769 0.192 4.853 0.216 ;
     RECT  0.857 21.552 5.648 21.576 ;
     RECT  5.648 0.528 5.752 42.672 ;
     RECT  5.752 0.528 5.944 42.402 ;
     RECT  5.944 4.992 6.275 5.016 ;
     RECT  5.944 36.528 6.275 36.552 ;
     RECT  5.944 39.36 6.275 39.384 ;
     RECT  6.325 0.192 6.755 0.216 ;
     RECT  5.944 34.368 6.803 34.392 ;
     RECT  5.944 28.512 6.851 28.872 ;
     RECT  6.851 28.848 6.941 28.872 ;
     RECT  5.944 21.072 7.052 21.096 ;
     RECT  7.052 12.864 7.139 12.888 ;
     RECT  7.052 20.976 7.139 21.096 ;
     RECT  7.139 21.072 7.337 21.096 ;
     RECT  7.333 12.72 7.417 12.744 ;
     RECT  7.868 39.072 7.955 39.096 ;
     RECT  7.957 4.992 8.201 5.016 ;
     RECT  8.54 26.112 8.627 26.136 ;
     RECT  8.557 42.192 8.675 42.216 ;
     RECT  8.485 33.024 8.741 33.048 ;
     RECT  8.629 1.152 8.993 1.176 ;
     RECT  8.965 28.272 9.052 28.296 ;
     RECT  8.989 30.72 9.073 30.744 ;
     RECT  8.773 35.328 9.107 35.352 ;
     RECT  9.061 32.928 9.203 32.952 ;
     RECT  9.157 30.528 9.244 30.552 ;
     RECT  9.349 35.376 9.443 35.4 ;
     RECT  9.925 26.112 10.012 26.136 ;
     RECT  10.837 33.312 11.048 33.336 ;
     RECT  10.837 37.584 11.048 37.608 ;
     RECT  11.048 0.528 11.152 42.672 ;
     RECT  11.152 0.798 11.344 42.402 ;
     RECT  11.344 22.176 11.987 22.2 ;
     RECT  12.469 42.624 12.589 42.648 ;
     RECT  12.589 42.192 12.665 42.648 ;
     RECT  12.665 42.192 13.475 42.216 ;
     RECT  13.093 21.936 16.448 21.96 ;
     RECT  16.448 0.528 16.552 42.672 ;
     RECT  16.552 0.798 16.744 42.402 ;
     RECT  16.744 21.936 21.848 21.96 ;
     RECT  21.848 0.528 21.952 42.672 ;
     RECT  21.952 0.798 22.144 42.402 ;
     RECT  22.144 21.936 22.853 22.056 ;
     RECT  22.853 22.032 27.248 22.056 ;
     RECT  27.248 0.528 27.352 42.672 ;
     RECT  27.352 0.798 27.544 42.402 ;
     RECT  27.544 21.936 27.683 22.152 ;
     RECT  27.683 21.936 28.037 22.056 ;
     RECT  28.037 21.936 32.648 21.96 ;
     RECT  32.648 0.528 32.752 42.672 ;
     RECT  32.752 0.798 32.944 42.402 ;
     RECT  32.944 21.936 38.048 21.96 ;
     RECT  38.048 0.528 38.152 42.672 ;
     RECT  38.152 0.798 38.344 42.402 ;
     RECT  38.344 21.936 42.181 21.96 ;
     RECT  42.181 21.552 43.02 21.96 ;
    LAYER M5 ;
     RECT  4.8 0.144 4.824 0.227 ;
     RECT  6.72 0.144 6.744 0.227 ;
     RECT  0.24 0.517 0.36 0.787 ;
     RECT  11.04 0.517 11.16 0.787 ;
     RECT  16.44 0.517 16.56 0.787 ;
     RECT  21.84 0.517 21.96 0.787 ;
     RECT  27.24 0.517 27.36 0.787 ;
     RECT  32.64 0.517 32.76 0.787 ;
     RECT  38.04 0.517 38.16 0.787 ;
     RECT  8.64 0.144 8.664 1.187 ;
     RECT  5.64 0.517 5.952 4.981 ;
     RECT  5.64 4.981 6.264 5.065 ;
     RECT  7.968 4.981 7.992 5.065 ;
     RECT  7.344 12.709 7.368 12.793 ;
     RECT  7.104 12.819 7.128 12.907 ;
     RECT  5.64 5.065 5.952 21.023 ;
     RECT  7.104 20.947 7.128 21.023 ;
     RECT  5.64 21.023 7.128 21.035 ;
     RECT  5.64 21.035 6.888 21.107 ;
     RECT  27.24 0.787 27.552 21.925 ;
     RECT  42.192 21.541 42.216 21.995 ;
     RECT  27.24 21.925 27.912 22.009 ;
     RECT  11.04 0.787 11.352 22.165 ;
     RECT  11.04 22.165 11.976 22.251 ;
     RECT  27.24 22.009 27.672 22.251 ;
     RECT  8.592 26.067 8.616 26.155 ;
     RECT  9.936 26.067 9.96 26.155 ;
     RECT  5.64 21.107 5.952 28.405 ;
     RECT  8.976 28.261 9 28.459 ;
     RECT  5.64 28.405 6.84 28.837 ;
     RECT  5.64 28.837 6.888 29.035 ;
     RECT  9.168 30.453 9.192 30.563 ;
     RECT  9.024 30.675 9.048 30.763 ;
     RECT  9.168 32.757 9.192 32.917 ;
     RECT  9.072 32.917 9.192 32.963 ;
     RECT  9.072 32.963 9.096 33.003 ;
     RECT  8.496 33.013 8.52 33.097 ;
     RECT  11.04 22.251 11.352 33.263 ;
     RECT  10.848 33.263 11.352 33.347 ;
     RECT  5.64 29.035 5.952 34.323 ;
     RECT  5.64 34.323 6.792 34.411 ;
     RECT  9.072 35.317 9.432 35.401 ;
     RECT  9.408 35.401 9.432 35.411 ;
     RECT  5.64 34.411 5.952 36.469 ;
     RECT  5.64 36.469 6.264 36.563 ;
     RECT  11.04 33.347 11.352 37.535 ;
     RECT  10.848 37.535 11.352 37.619 ;
     RECT  5.64 36.563 5.952 39.157 ;
     RECT  7.92 39.061 7.944 39.211 ;
     RECT  5.64 39.157 6.264 39.395 ;
     RECT  5.64 39.395 5.952 42.165 ;
     RECT  0.24 0.787 0.552 42.413 ;
     RECT  11.04 37.619 11.352 42.413 ;
     RECT  16.44 0.787 16.752 42.413 ;
     RECT  21.84 0.787 22.152 42.413 ;
     RECT  27.24 22.251 27.552 42.413 ;
     RECT  32.64 0.787 32.952 42.413 ;
     RECT  38.04 0.787 38.352 42.413 ;
     RECT  13.44 42.181 13.464 42.613 ;
     RECT  0.24 42.413 0.36 42.683 ;
     RECT  4.8 42.165 6.744 42.683 ;
     RECT  11.04 42.413 11.16 42.683 ;
     RECT  16.44 42.413 16.56 42.683 ;
     RECT  21.84 42.413 21.96 42.683 ;
     RECT  27.24 42.413 27.36 42.683 ;
     RECT  32.64 42.413 32.76 42.683 ;
     RECT  38.04 42.413 38.16 42.683 ;
     RECT  4.8 42.683 4.824 43.024 ;
     RECT  6.72 42.683 6.744 43.024 ;
     RECT  8.64 42.181 8.664 43.024 ;
     RECT  12.48 42.613 13.464 43.024 ;
    LAYER M6 ;
     RECT  0 33.396 4.789 34.26 ;
     RECT  4.789 42.176 4.858 42.208 ;
     RECT  4.789 33.024 6.757 34.26 ;
     RECT  0 27.996 6.773 28.86 ;
     RECT  6.757 33.024 6.827 34.4 ;
     RECT  6.229 36.48 6.827 36.512 ;
     RECT  6.773 27.996 6.899 29.024 ;
     RECT  0 11.796 6.901 12.66 ;
     RECT  6.773 21.056 6.955 21.088 ;
     RECT  6.901 11.796 7.139 12.896 ;
     RECT  7.074 20.992 7.147 21.024 ;
     RECT  6.709 42.176 7.147 42.208 ;
     RECT  7.139 11.796 7.403 12.768 ;
     RECT  6.229 4.992 8.003 5.024 ;
     RECT  6.827 33.024 9.013 34.26 ;
     RECT  9.013 32.768 9.061 34.26 ;
     RECT  9.013 30.72 9.077 30.752 ;
     RECT  9.077 30.464 9.082 30.752 ;
     RECT  9.082 30.464 9.203 30.496 ;
     RECT  9.061 32.768 9.203 35.36 ;
     RECT  0 38.796 9.397 39.66 ;
     RECT  9.203 33.28 9.466 35.36 ;
     RECT  8.565 26.112 9.971 26.144 ;
     RECT  9.466 33.28 10.883 34.26 ;
     RECT  9.397 37.568 10.883 39.66 ;
     RECT  0 22.596 11.941 23.46 ;
     RECT  11.941 22.208 27.877 23.46 ;
     RECT  27.877 21.952 42.227 23.46 ;
     RECT  0 0.996 43.2 1.86 ;
     RECT  0 6.396 43.2 7.26 ;
     RECT  7.403 11.796 43.2 12.66 ;
     RECT  0 17.196 43.2 18.06 ;
     RECT  42.227 22.596 43.2 23.46 ;
     RECT  6.899 27.996 43.2 28.86 ;
     RECT  10.883 33.396 43.2 34.26 ;
     RECT  10.883 38.796 43.2 39.66 ;
    LAYER M7 ;
     RECT  6.256 0.531 6.544 4.981 ;
     RECT  6.256 4.981 7.392 12.779 ;
     RECT  6.256 12.779 6.944 20.981 ;
     RECT  8.576 26.101 8.608 28.405 ;
     RECT  8.576 28.405 9.12 28.459 ;
     RECT  9.088 28.459 9.12 30.507 ;
     RECT  9.024 30.709 9.056 32.811 ;
     RECT  9.088 32.949 9.12 33.269 ;
     RECT  9.088 33.269 9.44 35.371 ;
     RECT  9.408 35.371 9.44 39.211 ;
     RECT  4.8 33.013 4.832 42.219 ;
     RECT  6.256 20.981 7.136 42.219 ;
     RECT  0.856 0.531 1.144 42.669 ;
     RECT  6.256 42.219 6.544 42.669 ;
     RECT  11.656 0.531 11.944 42.669 ;
     RECT  17.056 0.531 17.344 42.669 ;
     RECT  22.456 0.531 22.744 42.669 ;
     RECT  27.856 0.531 28.144 42.669 ;
     RECT  33.256 0.531 33.544 42.669 ;
     RECT  38.656 0.531 38.944 42.669 ;
  END
END dsfd_ctrl_ctr
END LIBRARY
